One B-rep face of a CAD part: STEP entity #79398.
In plain terms, the planar face has unit normal (0, 0, 1).
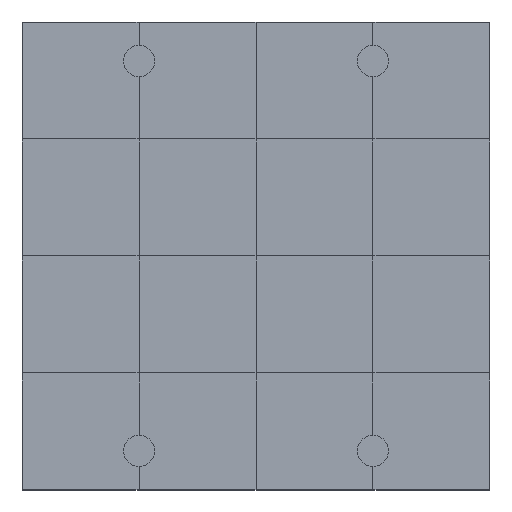
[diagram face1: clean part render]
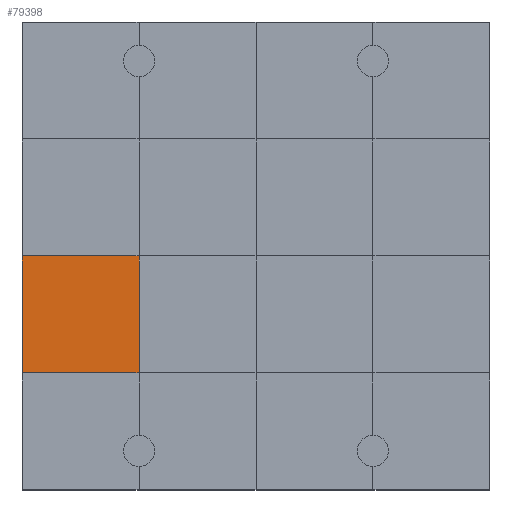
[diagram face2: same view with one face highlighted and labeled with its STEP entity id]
Its self-contained STEP definition (entity closure, numbers rounded to 3 decimals):
#78948 = VERTEX_POINT('',#78949);
#78949 = CARTESIAN_POINT('',(0.,3.,1.2));
#78963 = PLANE('',#78964);
#78964 = AXIS2_PLACEMENT_3D('',#78965,#78966,#78967);
#78965 = CARTESIAN_POINT('',(0.,3.,0.));
#78966 = DIRECTION('',(1.,0.,-0.));
#78967 = DIRECTION('',(0.,0.,1.));
#78989 = PLANE('',#78990);
#78990 = AXIS2_PLACEMENT_3D('',#78991,#78992,#78993);
#78991 = CARTESIAN_POINT('',(0.,0.,1.2));
#78992 = DIRECTION('',(0.,0.,1.));
#78993 = DIRECTION('',(1.,0.,-0.));
#79140 = VERTEX_POINT('',#79141);
#79141 = CARTESIAN_POINT('',(3.,3.,1.2));
#79162 = EDGE_CURVE('',#78948,#79140,#79163,.T.);
#79163 = SURFACE_CURVE('',#79164,(#79168,#79175),.PCURVE_S1.);
#79164 = LINE('',#79165,#79166);
#79165 = CARTESIAN_POINT('',(0.,3.,1.2));
#79166 = VECTOR('',#79167,1.);
#79167 = DIRECTION('',(1.,0.,-0.));
#79168 = PCURVE('',#78989,#79169);
#79169 = DEFINITIONAL_REPRESENTATION('',(#79170),#79174);
#79170 = LINE('',#79171,#79172);
#79171 = CARTESIAN_POINT('',(0.,3.));
#79172 = VECTOR('',#79173,1.);
#79173 = DIRECTION('',(1.,0.));
#79174 = ( GEOMETRIC_REPRESENTATION_CONTEXT(2) 
PARAMETRIC_REPRESENTATION_CONTEXT() REPRESENTATION_CONTEXT('2D SPACE',''
  ) );
#79175 = PCURVE('',#79176,#79181);
#79176 = PLANE('',#79177);
#79177 = AXIS2_PLACEMENT_3D('',#79178,#79179,#79180);
#79178 = CARTESIAN_POINT('',(0.,3.,1.2));
#79179 = DIRECTION('',(0.,0.,1.));
#79180 = DIRECTION('',(1.,0.,-0.));
#79181 = DEFINITIONAL_REPRESENTATION('',(#79182),#79186);
#79182 = LINE('',#79183,#79184);
#79183 = CARTESIAN_POINT('',(0.,0.));
#79184 = VECTOR('',#79185,1.);
#79185 = DIRECTION('',(1.,0.));
#79186 = ( GEOMETRIC_REPRESENTATION_CONTEXT(2) 
PARAMETRIC_REPRESENTATION_CONTEXT() REPRESENTATION_CONTEXT('2D SPACE',''
  ) );
#79221 = VERTEX_POINT('',#79222);
#79222 = CARTESIAN_POINT('',(0.,6.,1.2));
#79248 = EDGE_CURVE('',#78948,#79221,#79249,.T.);
#79249 = SURFACE_CURVE('',#79250,(#79254,#79261),.PCURVE_S1.);
#79250 = LINE('',#79251,#79252);
#79251 = CARTESIAN_POINT('',(0.,3.,1.2));
#79252 = VECTOR('',#79253,1.);
#79253 = DIRECTION('',(-0.,1.,0.));
#79254 = PCURVE('',#78963,#79255);
#79255 = DEFINITIONAL_REPRESENTATION('',(#79256),#79260);
#79256 = LINE('',#79257,#79258);
#79257 = CARTESIAN_POINT('',(1.2,0.));
#79258 = VECTOR('',#79259,1.);
#79259 = DIRECTION('',(0.,-1.));
#79260 = ( GEOMETRIC_REPRESENTATION_CONTEXT(2) 
PARAMETRIC_REPRESENTATION_CONTEXT() REPRESENTATION_CONTEXT('2D SPACE',''
  ) );
#79261 = PCURVE('',#79176,#79262);
#79262 = DEFINITIONAL_REPRESENTATION('',(#79263),#79267);
#79263 = LINE('',#79264,#79265);
#79264 = CARTESIAN_POINT('',(0.,0.));
#79265 = VECTOR('',#79266,1.);
#79266 = DIRECTION('',(0.,1.));
#79267 = ( GEOMETRIC_REPRESENTATION_CONTEXT(2) 
PARAMETRIC_REPRESENTATION_CONTEXT() REPRESENTATION_CONTEXT('2D SPACE',''
  ) );
#79398 = ADVANCED_FACE('',(#79399),#79176,.T.);
#79399 = FACE_BOUND('',#79400,.T.);
#79400 = EDGE_LOOP('',(#79401,#79402,#79403,#79431));
#79401 = ORIENTED_EDGE('',*,*,#79248,.F.);
#79402 = ORIENTED_EDGE('',*,*,#79162,.T.);
#79403 = ORIENTED_EDGE('',*,*,#79404,.T.);
#79404 = EDGE_CURVE('',#79140,#79405,#79407,.T.);
#79405 = VERTEX_POINT('',#79406);
#79406 = CARTESIAN_POINT('',(3.,6.,1.2));
#79407 = SURFACE_CURVE('',#79408,(#79412,#79419),.PCURVE_S1.);
#79408 = LINE('',#79409,#79410);
#79409 = CARTESIAN_POINT('',(3.,3.,1.2));
#79410 = VECTOR('',#79411,1.);
#79411 = DIRECTION('',(-0.,1.,0.));
#79412 = PCURVE('',#79176,#79413);
#79413 = DEFINITIONAL_REPRESENTATION('',(#79414),#79418);
#79414 = LINE('',#79415,#79416);
#79415 = CARTESIAN_POINT('',(3.,0.));
#79416 = VECTOR('',#79417,1.);
#79417 = DIRECTION('',(0.,1.));
#79418 = ( GEOMETRIC_REPRESENTATION_CONTEXT(2) 
PARAMETRIC_REPRESENTATION_CONTEXT() REPRESENTATION_CONTEXT('2D SPACE',''
  ) );
#79419 = PCURVE('',#79420,#79425);
#79420 = PLANE('',#79421);
#79421 = AXIS2_PLACEMENT_3D('',#79422,#79423,#79424);
#79422 = CARTESIAN_POINT('',(3.,3.,1.2));
#79423 = DIRECTION('',(0.,0.,1.));
#79424 = DIRECTION('',(1.,0.,-0.));
#79425 = DEFINITIONAL_REPRESENTATION('',(#79426),#79430);
#79426 = LINE('',#79427,#79428);
#79427 = CARTESIAN_POINT('',(0.,0.));
#79428 = VECTOR('',#79429,1.);
#79429 = DIRECTION('',(0.,1.));
#79430 = ( GEOMETRIC_REPRESENTATION_CONTEXT(2) 
PARAMETRIC_REPRESENTATION_CONTEXT() REPRESENTATION_CONTEXT('2D SPACE',''
  ) );
#79431 = ORIENTED_EDGE('',*,*,#79432,.F.);
#79432 = EDGE_CURVE('',#79221,#79405,#79433,.T.);
#79433 = SURFACE_CURVE('',#79434,(#79438,#79445),.PCURVE_S1.);
#79434 = LINE('',#79435,#79436);
#79435 = CARTESIAN_POINT('',(0.,6.,1.2));
#79436 = VECTOR('',#79437,1.);
#79437 = DIRECTION('',(1.,0.,-0.));
#79438 = PCURVE('',#79176,#79439);
#79439 = DEFINITIONAL_REPRESENTATION('',(#79440),#79444);
#79440 = LINE('',#79441,#79442);
#79441 = CARTESIAN_POINT('',(0.,3.));
#79442 = VECTOR('',#79443,1.);
#79443 = DIRECTION('',(1.,0.));
#79444 = ( GEOMETRIC_REPRESENTATION_CONTEXT(2) 
PARAMETRIC_REPRESENTATION_CONTEXT() REPRESENTATION_CONTEXT('2D SPACE',''
  ) );
#79445 = PCURVE('',#79446,#79451);
#79446 = PLANE('',#79447);
#79447 = AXIS2_PLACEMENT_3D('',#79448,#79449,#79450);
#79448 = CARTESIAN_POINT('',(0.,6.,1.2));
#79449 = DIRECTION('',(0.,0.,1.));
#79450 = DIRECTION('',(1.,0.,-0.));
#79451 = DEFINITIONAL_REPRESENTATION('',(#79452),#79456);
#79452 = LINE('',#79453,#79454);
#79453 = CARTESIAN_POINT('',(0.,0.));
#79454 = VECTOR('',#79455,1.);
#79455 = DIRECTION('',(1.,0.));
#79456 = ( GEOMETRIC_REPRESENTATION_CONTEXT(2) 
PARAMETRIC_REPRESENTATION_CONTEXT() REPRESENTATION_CONTEXT('2D SPACE',''
  ) );
